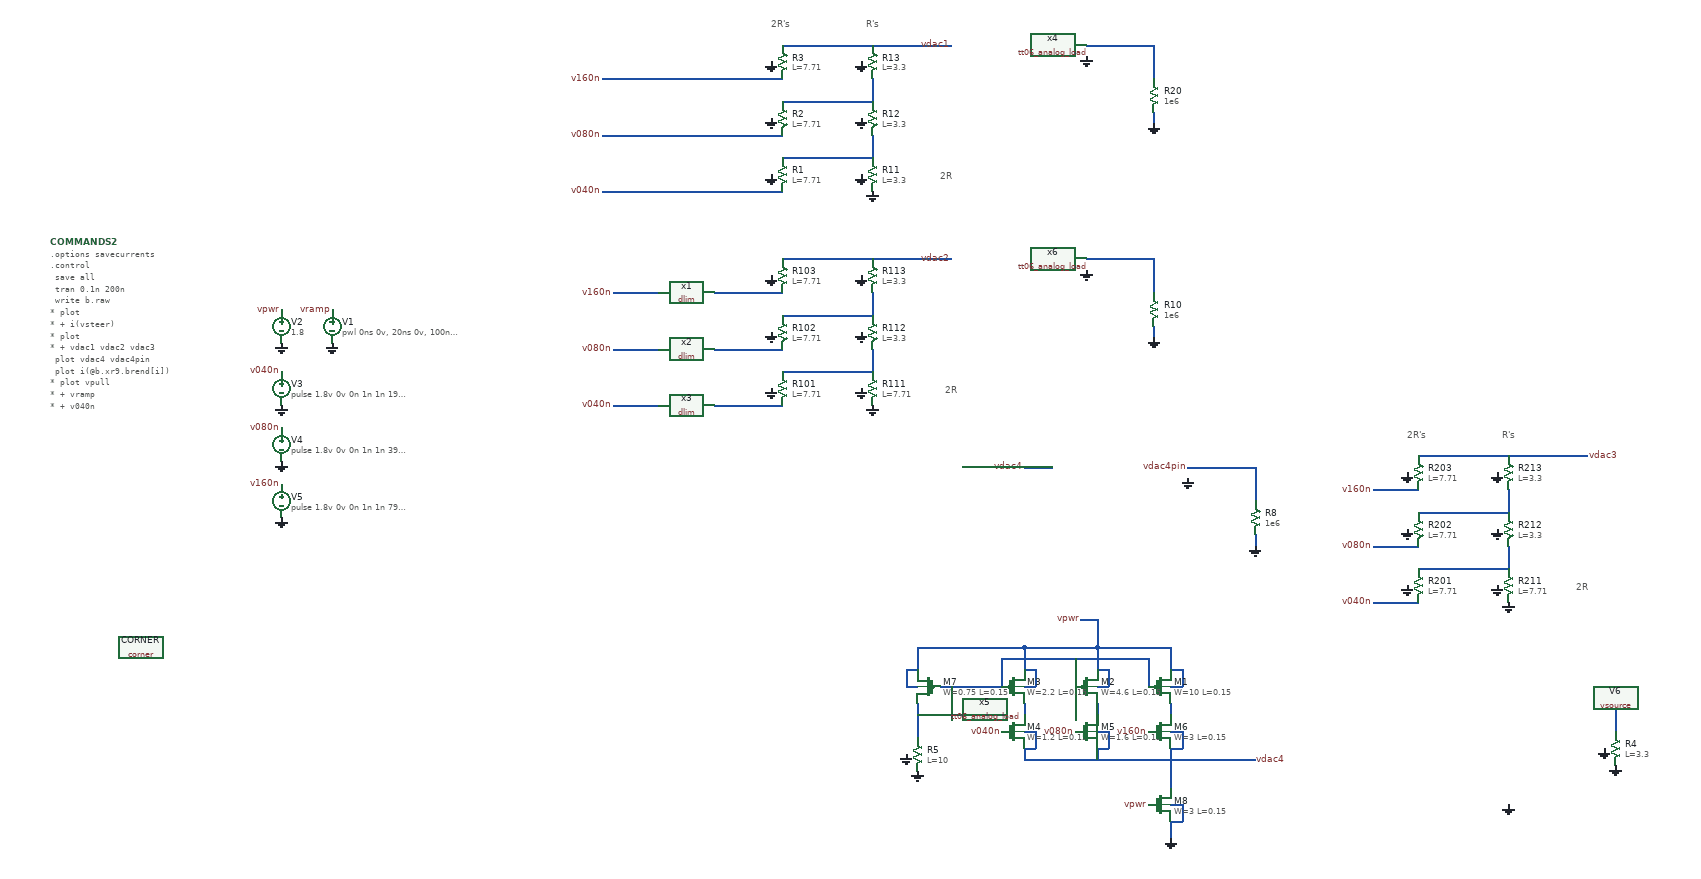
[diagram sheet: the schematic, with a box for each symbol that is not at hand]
v {xschem version=3.4.5 file_version=1.2
}
G {}
K {}
V {}
S {}
E {}
B 2 0 170 980 720 {flags=graph
y1=-0.00056745871
y2=0.00058338929
ypos1=0
ypos2=2
divy=5
subdivy=4
unity=1
x1=1.2582098e-08
x2=2.125821e-07
divx=5
subdivx=1
xlabmag=1.0
ylabmag=1.0


dataset=-1
unitx=1
logx=0
logy=0
rainbow=1




color="7 4"
node="i(@b.xr5.brend[i])
i(@b.xr4.brend[i])"}
T {2R's} 1140 -1310 0 0 0.4 0.4 {}
T {R's} 1310 -1310 0 0 0.4 0.4 {}
T {2R} 1440 -1040 0 0 0.4 0.4 {}
T {2R} 1450 -660 0 0 0.4 0.4 {}
T {2R's} 2270 -580 0 0 0.4 0.4 {}
T {R's} 2440 -580 0 0 0.4 0.4 {}
T {2R} 2570 -310 0 0 0.4 0.4 {}
N 1160 -1060 1320 -1060 {
lab=#net1}
N 1080 -1000 1160 -1000 {
lab=v040n}
N 1160 -1160 1320 -1160 {
lab=#net2}
N 1080 -1100 1160 -1100 {
lab=v080n}
N 1320 -1100 1320 -1060 {
lab=#net1}
N 1080 -1200 1160 -1200 {
lab=v160n}
N 1320 -1200 1320 -1160 {
lab=#net2}
N 1160 -1260 1320 -1260 {
lab=vdac1}
N 1320 -1260 1460 -1260 {
lab=vdac1}
N 1160 -680 1320 -680 {
lab=#net3}
N 2210 -270 2290 -270 {
lab=v040n}
N 1160 -780 1320 -780 {
lab=#net4}
N 2210 -370 2290 -370 {
lab=v080n}
N 1320 -720 1320 -680 {
lab=#net3}
N 2210 -470 2290 -470 {
lab=v160n}
N 1320 -820 1320 -780 {
lab=#net4}
N 1160 -880 1320 -880 {
lab=vdac2}
N 1320 -880 1460 -880 {
lab=vdac2}
N 1700 -880 1740 -880 {
lab=#net5}
N 1820 -760 1820 -740 {
lab=GND}
N 1820 -880 1820 -820 {
lab=#net5}
N 1740 -880 1820 -880 {
lab=#net5}
N 2290 -330 2450 -330 {
lab=#net6}
N 860 -620 940 -620 {
lab=v040n}
N 2290 -430 2450 -430 {
lab=#net7}
N 860 -720 940 -720 {
lab=v080n}
N 2450 -370 2450 -330 {
lab=#net6}
N 860 -820 940 -820 {
lab=v160n}
N 2450 -470 2450 -430 {
lab=#net7}
N 2290 -530 2450 -530 {
lab=vdac3}
N 2450 -530 2590 -530 {
lab=vdac3}
N 900 -1200 1080 -1200 {
lab=v160n
color=3}
N 900 -1100 1080 -1100 {
lab=v080n
color=3}
N 900 -1000 1080 -1000 {
lab=v040n
color=3}
N 1700 -1260 1740 -1260 {
lab=#net8}
N 1820 -1140 1820 -1120 {
lab=GND}
N 1820 -1260 1820 -1200 {
lab=#net8}
N 1740 -1260 1820 -1260 {
lab=#net8}
N 840 -1200 900 -1200 {
lab=v160n}
N 840 -1100 900 -1100 {
lab=v080n}
N 840 -1000 900 -1000 {
lab=v040n}
N 1040 -820 1160 -820 {
lab=#net9}
N 1040 -720 1160 -720 {
lab=#net10}
N 1040 -620 1160 -620 {
lab=#net11}
N 1880 -510 1920 -510 {
lab=vdac4pin}
N 2000 -390 2000 -370 {
lab=GND}
N 2000 -510 2000 -450 {
lab=vdac4pin}
N 1920 -510 2000 -510 {
lab=vdac4pin}
N 1590 -510 1640 -510 {
lab=vdac4}
N 1590 -190 1590 -150 {
lab=vpwr}
N 1590 -190 1720 -190 {
lab=vpwr}
N 1720 -190 1850 -190 {
lab=vpwr}
N 1850 -190 1850 -150 {
lab=vpwr}
N 1720 -190 1720 -150 {
lab=vpwr}
N 1690 -240 1720 -240 {
lab=vpwr}
N 1720 -240 1720 -190 {
lab=vpwr}
N 1590 -120 1610 -120 {
lab=vpwr}
N 1610 -150 1610 -120 {
lab=vpwr}
N 1590 -150 1610 -150 {
lab=vpwr}
N 1720 -150 1740 -150 {
lab=vpwr}
N 1740 -150 1740 -120 {
lab=vpwr}
N 1720 -120 1740 -120 {
lab=vpwr}
N 1850 -120 1870 -120 {
lab=vpwr}
N 1870 -150 1870 -120 {
lab=vpwr}
N 1850 -150 1870 -150 {
lab=vpwr}
N 1550 -170 1810 -170 {
lab=#net12}
N 1810 -170 1810 -120 {
lab=#net12}
N 1680 -170 1680 -120 {
lab=#net12}
N 1550 -170 1550 -120 {
lab=#net12}
N 1590 -90 1590 -70 {
lab=#net13}
N 1720 -90 1720 -70 {
lab=#net14}
N 1850 -90 1850 -70 {
lab=#net15}
N 1590 -10 1590 10 {
lab=vdac4}
N 1590 10 1850 10 {
lab=vdac4}
N 1850 -10 1850 10 {
lab=vdac4}
N 1720 -10 1720 10 {
lab=vdac4}
N 1440 -120 1550 -120 {
lab=#net12}
N 1850 10 2000 10 {
lab=vdac4}
N 1400 -90 1400 -30 {
lab=#net12}
N 1400 -70 1460 -70 {
lab=#net12}
N 1460 -120 1460 -70 {
lab=#net12}
N 1400 -190 1400 -150 {
lab=vpwr}
N 1400 -190 1590 -190 {
lab=vpwr}
N 1590 -40 1610 -40 {
lab=vdac4}
N 1720 -40 1740 -40 {
lab=vdac4}
N 1850 -40 1870 -40 {
lab=vdac4}
N 1380 -120 1400 -120 {
lab=vpwr}
N 1380 -150 1380 -120 {
lab=vpwr}
N 1380 -150 1400 -150 {
lab=vpwr}
N 1610 -40 1610 -10 {
lab=vdac4}
N 1590 -10 1610 -10 {
lab=vdac4}
N 1740 -40 1740 -10 {
lab=vdac4}
N 1720 -10 1740 -10 {
lab=vdac4}
N 1870 -40 1870 -10 {
lab=vdac4}
N 1850 -10 1870 -10 {
lab=vdac4}
N 2640 -80 2640 -40 {
lab=#net16}
N 1850 90 1870 90 {
lab=GND}
N 1870 90 1870 120 {
lab=GND}
N 1850 120 1870 120 {
lab=GND}
N 1850 10 1850 60 {
lab=vdac4}
N 1850 120 1850 150 {
lab=GND}
C {sky130_fd_pr/corner.sym} 20 -190 0 0 {name=CORNER only_toplevel=true corner=tt}
C {devices/launcher.sym} 90 -50 0 0 {name=h17 
descr="Load waves" 
tclcommand="
xschem raw_read $netlist_dir/[file tail [file rootname [xschem get current_name]]].raw tran

"
}
C {devices/vsource.sym} 360 -760 0 0 {name=V1 value="pwl 0ns 0v, 20ns 0v, 100ns 1.8v, 200ns 1.8v"  savecurrent=false}
C {devices/lab_pin.sym} 360 -790 0 0 {name=p1 sig_type=std_logic lab=vramp}
C {devices/gnd.sym} 360 -730 0 0 {name=l2 lab=GND}
C {devices/vsource.sym} 270 -760 0 0 {name=V2 value=1.8  savecurrent=false}
C {devices/lab_pin.sym} 270 -790 0 0 {name=p7 sig_type=std_logic lab=vpwr}
C {devices/gnd.sym} 270 -730 0 0 {name=l3 lab=GND}
C {devices/simulator_commands_shown.sym} -140 -910 0 0 {name=COMMANDS2
simulator=ngspice
only_toplevel=false 
value="

.options savecurrents

.control
  save all
  tran 0.1n 200n
  write b.raw
*  plot
*  + i(vsteer)
*  plot
*  + vdac1 vdac2 vdac3
  plot vdac4 vdac4pin
  plot i(@b.xr9.brend[i])
*  plot vpull
*  + vramp
*  + v040n
*  + v080n+2
*  + v160n+4
*  + (v160n/2.0+v080n/4.0+v040n/8.0)
.endc

"}
C {devices/vsource.sym} 270 -650 0 0 {name=V3 value="pulse 1.8v 0v 0n 1n 1n 19n 40n"  savecurrent=false}
C {devices/lab_pin.sym} 270 -680 0 0 {name=p3 sig_type=std_logic lab=v040n}
C {devices/gnd.sym} 270 -620 0 0 {name=l4 lab=GND}
C {devices/vsource.sym} 270 -550 0 0 {name=V4 value="pulse 1.8v 0v 0n 1n 1n 39n 80n"  savecurrent=false}
C {devices/lab_pin.sym} 270 -580 0 0 {name=p5 sig_type=std_logic lab=v080n}
C {devices/gnd.sym} 270 -520 0 0 {name=l5 lab=GND}
C {devices/vsource.sym} 270 -450 0 0 {name=V5 value="pulse 1.8v 0v 0n 1n 1n 79n 160n"  savecurrent=false}
C {devices/lab_pin.sym} 270 -480 0 0 {name=p6 sig_type=std_logic lab=v160n}
C {devices/gnd.sym} 270 -420 0 0 {name=l6 lab=GND}
C {sky130_fd_pr/res_high_po_1p41.sym} 1320 -1130 0 0 {name=R12
L=3.3
model=res_high_po_1p41
spiceprefix=X
mult=1}
C {sky130_fd_pr/res_high_po_1p41.sym} 1160 -1030 0 0 {name=R1
L=7.71
model=res_high_po_1p41
spiceprefix=X
mult=1}
C {sky130_fd_pr/res_high_po_1p41.sym} 1320 -1030 0 0 {name=R11
L=3.3
model=res_high_po_1p41
spiceprefix=X
mult=1}
C {devices/gnd.sym} 1320 -1000 0 0 {name=l7 lab=GND}
C {devices/gnd.sym} 1300 -1030 0 1 {name=l8 lab=GND}
C {devices/gnd.sym} 1300 -1130 0 1 {name=l9 lab=GND}
C {devices/gnd.sym} 1140 -1030 0 1 {name=l10 lab=GND}
C {devices/lab_pin.sym} 840 -1000 0 0 {name=p4 sig_type=std_logic lab=v040n}
C {sky130_fd_pr/res_high_po_1p41.sym} 1160 -1130 0 0 {name=R2
L=7.71
model=res_high_po_1p41
spiceprefix=X
mult=1}
C {devices/gnd.sym} 1140 -1130 0 1 {name=l11 lab=GND}
C {devices/lab_pin.sym} 840 -1100 0 0 {name=p9 sig_type=std_logic lab=v080n}
C {sky130_fd_pr/res_high_po_1p41.sym} 1320 -1230 0 0 {name=R13
L=3.3
model=res_high_po_1p41
spiceprefix=X
mult=1}
C {devices/gnd.sym} 1300 -1230 0 1 {name=l12 lab=GND}
C {sky130_fd_pr/res_high_po_1p41.sym} 1160 -1230 0 0 {name=R3
L=7.71
model=res_high_po_1p41
spiceprefix=X
mult=1}
C {devices/gnd.sym} 1140 -1230 0 1 {name=l13 lab=GND}
C {devices/lab_pin.sym} 840 -1200 0 0 {name=p10 sig_type=std_logic lab=v160n}
C {devices/lab_pin.sym} 1460 -1260 3 1 {name=p11 sig_type=std_logic lab=vdac1}
C {sky130_fd_pr/res_high_po_1p41.sym} 1320 -750 0 0 {name=R112
L=3.3
model=res_high_po_1p41
spiceprefix=X
mult=1}
C {sky130_fd_pr/res_high_po_1p41.sym} 1160 -650 0 0 {name=R101
L=7.71
model=res_high_po_1p41
spiceprefix=X
mult=1}
C {sky130_fd_pr/res_high_po_1p41.sym} 1320 -650 0 0 {name=R111
L=7.71
model=res_high_po_1p41
spiceprefix=X
mult=1}
C {devices/gnd.sym} 1320 -620 0 0 {name=l14 lab=GND}
C {devices/gnd.sym} 1300 -650 0 1 {name=l15 lab=GND}
C {devices/gnd.sym} 1300 -750 0 1 {name=l16 lab=GND}
C {devices/gnd.sym} 1140 -650 0 1 {name=l17 lab=GND}
C {devices/lab_pin.sym} 2210 -270 0 0 {name=p2 sig_type=std_logic lab=v040n}
C {sky130_fd_pr/res_high_po_1p41.sym} 1160 -750 0 0 {name=R102
L=7.71
model=res_high_po_1p41
spiceprefix=X
mult=1}
C {devices/gnd.sym} 1140 -750 0 1 {name=l18 lab=GND}
C {devices/lab_pin.sym} 2210 -370 0 0 {name=p12 sig_type=std_logic lab=v080n}
C {sky130_fd_pr/res_high_po_1p41.sym} 1320 -850 0 0 {name=R113
L=3.3
model=res_high_po_1p41
spiceprefix=X
mult=1}
C {devices/gnd.sym} 1300 -850 0 1 {name=l19 lab=GND}
C {sky130_fd_pr/res_high_po_1p41.sym} 1160 -850 0 0 {name=R103
L=7.71
model=res_high_po_1p41
spiceprefix=X
mult=1}
C {devices/gnd.sym} 1140 -850 0 1 {name=l20 lab=GND}
C {devices/lab_pin.sym} 2210 -470 0 0 {name=p13 sig_type=std_logic lab=v160n}
C {devices/lab_pin.sym} 1460 -880 3 1 {name=p14 sig_type=std_logic lab=vdac2}
C {tt06_analog_load.sym} 1550 -860 0 0 {name=x6}
C {devices/gnd.sym} 1700 -860 0 0 {name=l22 lab=GND}
C {devices/res.sym} 1820 -790 0 0 {name=R10
value=1e6
footprint=1206
device=resistor
m=1}
C {devices/gnd.sym} 1820 -740 0 0 {name=l23 lab=GND}
C {sky130_fd_pr/res_high_po_1p41.sym} 2450 -400 0 0 {name=R212
L=3.3
model=res_high_po_1p41
spiceprefix=X
mult=1}
C {sky130_fd_pr/res_high_po_1p41.sym} 2290 -300 0 0 {name=R201
L=7.71
model=res_high_po_1p41
spiceprefix=X
mult=1}
C {sky130_fd_pr/res_high_po_1p41.sym} 2450 -300 0 0 {name=R211
L=7.71
model=res_high_po_1p41
spiceprefix=X
mult=1}
C {devices/gnd.sym} 2450 -270 0 0 {name=l1 lab=GND}
C {devices/gnd.sym} 2430 -300 0 1 {name=l21 lab=GND}
C {devices/gnd.sym} 2430 -400 0 1 {name=l24 lab=GND}
C {devices/gnd.sym} 2270 -300 0 1 {name=l25 lab=GND}
C {devices/lab_pin.sym} 860 -620 0 0 {name=p8 sig_type=std_logic lab=v040n}
C {sky130_fd_pr/res_high_po_1p41.sym} 2290 -400 0 0 {name=R202
L=7.71
model=res_high_po_1p41
spiceprefix=X
mult=1}
C {devices/gnd.sym} 2270 -400 0 1 {name=l26 lab=GND}
C {devices/lab_pin.sym} 860 -720 0 0 {name=p15 sig_type=std_logic lab=v080n}
C {sky130_fd_pr/res_high_po_1p41.sym} 2450 -500 0 0 {name=R213
L=3.3
model=res_high_po_1p41
spiceprefix=X
mult=1}
C {devices/gnd.sym} 2430 -500 0 1 {name=l27 lab=GND}
C {sky130_fd_pr/res_high_po_1p41.sym} 2290 -500 0 0 {name=R203
L=7.71
model=res_high_po_1p41
spiceprefix=X
mult=1}
C {devices/gnd.sym} 2270 -500 0 1 {name=l28 lab=GND}
C {devices/lab_pin.sym} 860 -820 0 0 {name=p16 sig_type=std_logic lab=v160n}
C {devices/lab_pin.sym} 2590 -530 0 1 {name=p17 sig_type=std_logic lab=vdac3}
C {tt06_analog_load.sym} 1550 -1240 0 0 {name=x4}
C {devices/res.sym} 1820 -1170 0 0 {name=R20
value=1e6
footprint=1206
device=resistor
m=1}
C {devices/gnd.sym} 1820 -1120 0 0 {name=l29 lab=GND}
C {devices/gnd.sym} 1700 -1240 0 0 {name=l30 lab=GND}
C {dlim.sym} 990 -820 0 0 {name=x1}
C {dlim.sym} 990 -720 0 0 {name=x2}
C {dlim.sym} 990 -620 0 0 {name=x3}
C {devices/lab_pin.sym} 1590 -510 3 1 {name=p25 sig_type=std_logic lab=vdac4}
C {tt06_analog_load.sym} 1730 -490 0 0 {name=x5}
C {devices/gnd.sym} 1880 -490 0 0 {name=l41 lab=GND}
C {devices/res.sym} 2000 -420 0 0 {name=R8
value=1e6
footprint=1206
device=resistor
m=1}
C {devices/lab_pin.sym} 1880 -510 3 1 {name=p28 sig_type=std_logic lab=vdac4pin}
C {sky130_fd_pr/pfet_01v8.sym} 1830 -120 0 0 {name=M1
L=0.15
W=10
nf=1
mult=1
ad="'int((nf+1)/2) * W/nf * 0.29'" 
pd="'2*int((nf+1)/2) * (W/nf + 0.29)'"
as="'int((nf+2)/2) * W/nf * 0.29'" 
ps="'2*int((nf+2)/2) * (W/nf + 0.29)'"
nrd="'0.29 / W'" nrs="'0.29 / W'"
sa=0 sb=0 sd=0
model=pfet_01v8
spiceprefix=X
}
C {sky130_fd_pr/pfet_01v8.sym} 1700 -120 0 0 {name=M2
L=0.15
W=4.6
nf=1
mult=1
ad="'int((nf+1)/2) * W/nf * 0.29'" 
pd="'2*int((nf+1)/2) * (W/nf + 0.29)'"
as="'int((nf+2)/2) * W/nf * 0.29'" 
ps="'2*int((nf+2)/2) * (W/nf + 0.29)'"
nrd="'0.29 / W'" nrs="'0.29 / W'"
sa=0 sb=0 sd=0
model=pfet_01v8
spiceprefix=X
}
C {sky130_fd_pr/pfet_01v8.sym} 1570 -120 0 0 {name=M3
L=0.15
W=2.2
nf=1
mult=1
ad="'int((nf+1)/2) * W/nf * 0.29'" 
pd="'2*int((nf+1)/2) * (W/nf + 0.29)'"
as="'int((nf+2)/2) * W/nf * 0.29'" 
ps="'2*int((nf+2)/2) * (W/nf + 0.29)'"
nrd="'0.29 / W'" nrs="'0.29 / W'"
sa=0 sb=0 sd=0
model=pfet_01v8
spiceprefix=X
}
C {devices/lab_pin.sym} 1690 -240 0 0 {name=p21 sig_type=std_logic lab=vpwr}
C {devices/lab_pin.sym} 1550 -40 0 0 {name=p22 sig_type=std_logic lab=v040n}
C {devices/lab_pin.sym} 1680 -40 0 0 {name=p23 sig_type=std_logic lab=v080n}
C {devices/lab_pin.sym} 1810 -40 0 0 {name=p24 sig_type=std_logic lab=v160n}
C {sky130_fd_pr/pfet_01v8.sym} 1420 -120 0 1 {name=M7
L=0.15
W=0.75
nf=1
mult=1
ad="'int((nf+1)/2) * W/nf * 0.29'" 
pd="'2*int((nf+1)/2) * (W/nf + 0.29)'"
as="'int((nf+2)/2) * W/nf * 0.29'" 
ps="'2*int((nf+2)/2) * (W/nf + 0.29)'"
nrd="'0.29 / W'" nrs="'0.29 / W'"
sa=0 sb=0 sd=0
model=pfet_01v8
spiceprefix=X
}
C {devices/lab_pin.sym} 2000 10 0 1 {name=p26 sig_type=std_logic lab=vdac4}
C {sky130_fd_pr/res_high_po_1p41.sym} 1400 0 0 0 {name=R5
L=10
model=res_high_po_1p41
spiceprefix=X
mult=1}
C {devices/gnd.sym} 1400 30 0 1 {name=l31 lab=GND}
C {devices/gnd.sym} 1380 0 1 1 {name=l32 lab=GND}
C {devices/gnd.sym} 2000 -370 0 1 {name=l33 lab=GND}
C {sky130_fd_pr/nfet_01v8.sym} 1570 -40 0 0 {name=M4
L=0.15
W=1.2
nf=1 
mult=1
ad="'int((nf+1)/2) * W/nf * 0.29'" 
pd="'2*int((nf+1)/2) * (W/nf + 0.29)'"
as="'int((nf+2)/2) * W/nf * 0.29'" 
ps="'2*int((nf+2)/2) * (W/nf + 0.29)'"
nrd="'0.29 / W'" nrs="'0.29 / W'"
sa=0 sb=0 sd=0
model=nfet_01v8
spiceprefix=X
}
C {sky130_fd_pr/nfet_01v8.sym} 1700 -40 0 0 {name=M5
L=0.15
W=1.6
nf=1 
mult=1
ad="'int((nf+1)/2) * W/nf * 0.29'" 
pd="'2*int((nf+1)/2) * (W/nf + 0.29)'"
as="'int((nf+2)/2) * W/nf * 0.29'" 
ps="'2*int((nf+2)/2) * (W/nf + 0.29)'"
nrd="'0.29 / W'" nrs="'0.29 / W'"
sa=0 sb=0 sd=0
model=nfet_01v8
spiceprefix=X
}
C {sky130_fd_pr/nfet_01v8.sym} 1830 -40 0 0 {name=M6
L=0.15
W=3
nf=1 
mult=1
ad="'int((nf+1)/2) * W/nf * 0.29'" 
pd="'2*int((nf+1)/2) * (W/nf + 0.29)'"
as="'int((nf+2)/2) * W/nf * 0.29'" 
ps="'2*int((nf+2)/2) * (W/nf + 0.29)'"
nrd="'0.29 / W'" nrs="'0.29 / W'"
sa=0 sb=0 sd=0
model=nfet_01v8
spiceprefix=X
}
C {devices/vsource.sym} 2450 60 0 0 {name=V6 value=0 savecurrent=false}
C {devices/gnd.sym} 2450 90 0 1 {name=l34 lab=GND}
C {sky130_fd_pr/res_high_po_1p41.sym} 2640 -10 0 0 {name=R4
L=3.3
model=res_high_po_1p41
spiceprefix=X
mult=1}
C {devices/gnd.sym} 2620 -10 1 1 {name=l35 lab=GND}
C {devices/gnd.sym} 2640 20 0 1 {name=l36 lab=GND}
C {sky130_fd_pr/nfet_01v8.sym} 1830 90 0 0 {name=M8
L=0.15
W=3
nf=1 
mult=1
ad="'int((nf+1)/2) * W/nf * 0.29'" 
pd="'2*int((nf+1)/2) * (W/nf + 0.29)'"
as="'int((nf+2)/2) * W/nf * 0.29'" 
ps="'2*int((nf+2)/2) * (W/nf + 0.29)'"
nrd="'0.29 / W'" nrs="'0.29 / W'"
sa=0 sb=0 sd=0
model=nfet_01v8
spiceprefix=X
}
C {devices/gnd.sym} 1850 150 0 1 {name=l37 lab=GND}
C {devices/lab_pin.sym} 1810 90 0 0 {name=p18 sig_type=std_logic lab=vpwr}
